VERSION 5.7 ;
  NOWIREEXTENSIONATPIN ON ;
  DIVIDERCHAR "/" ;
  BUSBITCHARS "[]" ;
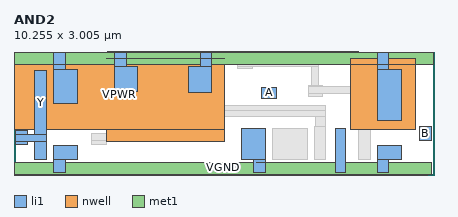
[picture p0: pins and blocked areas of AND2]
MACRO AND2
  CLASS BLOCK ;
  FOREIGN AND2 ;
  ORIGIN 7.870 2.670 ;
  SIZE 10.255 BY 3.005 ;
  PIN A
    ANTENNAGATEAREA 0.375000 ;
    PORT
      LAYER li1 ;
        RECT -1.815 -0.800 -1.460 -0.525 ;
    END
  END A
  PIN B
    ANTENNAGATEAREA 0.252000 ;
    PORT
      LAYER li1 ;
        RECT 2.040 -1.820 2.335 -1.480 ;
    END
  END B
  PIN VPWR
    USE POWER ;
    PORT
      LAYER nwell ;
        RECT -5.595 0.175 -2.740 0.185 ;
        RECT -5.600 0.170 -2.740 0.175 ;
        RECT -7.850 -1.560 -2.740 0.170 ;
        RECT 0.355 -1.560 1.925 0.180 ;
        RECT -5.600 -1.845 -2.740 -1.560 ;
      LAYER li1 ;
        RECT -6.905 -0.100 -6.615 0.330 ;
        RECT -5.415 -0.025 -5.125 0.335 ;
        RECT -3.320 -0.025 -3.045 0.335 ;
        RECT -6.905 -0.935 -6.310 -0.100 ;
        RECT -5.415 -0.640 -4.850 -0.025 ;
        RECT -3.605 -0.655 -3.045 -0.025 ;
        RECT 0.995 -0.100 1.285 0.330 ;
        RECT 0.995 -1.340 1.590 -0.100 ;
      LAYER met1 ;
        RECT -5.580 0.330 0.545 0.335 ;
        RECT -7.870 0.035 2.385 0.330 ;
        RECT -7.870 0.030 -5.570 0.035 ;
        RECT -2.780 0.030 2.385 0.035 ;
    END
  END VPWR
  PIN VGND
    USE GROUND ;
    PORT
      LAYER li1 ;
        RECT -6.905 -2.280 -6.310 -1.940 ;
        RECT -6.905 -2.610 -6.615 -2.280 ;
        RECT -2.310 -2.285 -1.725 -1.525 ;
        RECT -0.020 -1.530 0.215 -1.525 ;
        RECT -2.015 -2.620 -1.725 -2.285 ;
        RECT -0.030 -2.605 0.220 -1.530 ;
        RECT 0.995 -2.280 1.590 -1.940 ;
        RECT 0.995 -2.610 1.285 -2.280 ;
      LAYER met1 ;
        RECT -1.950 -2.370 -1.765 -2.365 ;
        RECT -7.850 -2.665 2.335 -2.370 ;
        RECT -7.850 -2.670 2.230 -2.665 ;
    END
  END VGND
  PIN Y
    ANTENNADIFFAREA 0.504000 ;
    PORT
      LAYER li1 ;
        RECT -7.840 -1.670 -7.535 -1.575 ;
        RECT -7.365 -1.670 -7.075 -0.120 ;
        RECT -7.840 -1.840 -7.075 -1.670 ;
        RECT -7.840 -1.915 -7.535 -1.840 ;
        RECT -7.365 -2.280 -7.075 -1.840 ;
    END
  END Y
  OBS
      LAYER li1 ;
        RECT -2.405 0.155 -2.050 0.210 ;
        RECT -4.630 -0.025 -4.355 0.000 ;
        RECT -2.405 -0.015 -0.430 0.155 ;
        RECT -4.630 -0.605 -3.815 -0.025 ;
        RECT -2.405 -0.065 -2.050 -0.015 ;
        RECT -0.605 -0.475 -0.430 -0.015 ;
        RECT -0.685 -0.510 -0.330 -0.475 ;
        RECT 0.535 -0.510 0.825 -0.120 ;
        RECT -4.630 -0.975 -4.355 -0.605 ;
        RECT -0.690 -0.690 0.825 -0.510 ;
        RECT -0.685 -0.750 -0.330 -0.690 ;
        RECT -4.630 -1.100 -0.270 -0.975 ;
        RECT -4.630 -1.235 -0.265 -1.100 ;
        RECT -4.630 -1.645 -4.355 -1.235 ;
        RECT -0.520 -1.485 -0.265 -1.235 ;
        RECT -1.265 -1.530 -0.710 -1.525 ;
        RECT -5.985 -1.830 -4.355 -1.645 ;
        RECT -5.985 -1.920 -5.600 -1.830 ;
        RECT -1.555 -2.280 -0.710 -1.530 ;
        RECT -1.555 -2.285 -1.265 -2.280 ;
        RECT -0.525 -2.290 -0.265 -1.485 ;
        RECT 0.535 -2.280 0.825 -0.690 ;
  END
END AND2
END LIBRARY

